# Generated by FakeRAM 2.0
VERSION 5.7 ;
BUSBITCHARS "[]" ;
PROPERTYDEFINITIONS
  MACRO width INTEGER ;
  MACRO depth INTEGER ;
  MACRO banks INTEGER ;
END PROPERTYDEFINITIONS
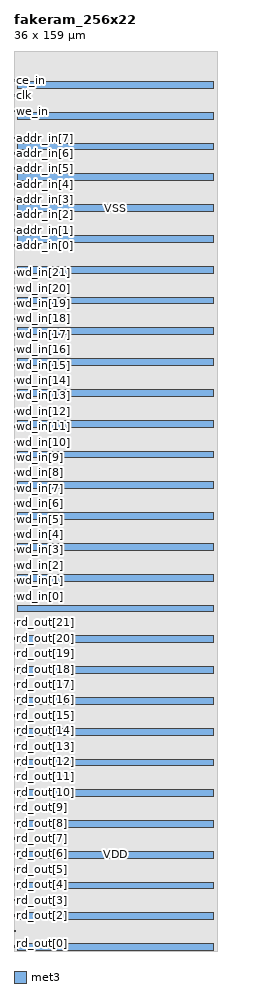
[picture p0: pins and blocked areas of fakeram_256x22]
MACRO fakeram_256x22
  PROPERTY width 22 ;
  PROPERTY depth 256 ;
  PROPERTY banks 1 ;
  FOREIGN fakeram_256x22 0 0 ;
  SYMMETRY X Y R90 ;
  SIZE 36.0000 BY 159.0000 ;
  CLASS BLOCK ;
  PIN rd_out[0]
    DIRECTION OUTPUT ;
    USE SIGNAL ;
    PORT
      LAYER met3 ;
      RECT 0.00000 0.68000 0.30000 0.98000 ;
    END
  END rd_out[0]
  PIN rd_out[1]
    DIRECTION OUTPUT ;
    USE SIGNAL ;
    PORT
      LAYER met3 ;
      RECT 0.00000 3.40000 0.30000 3.70000 ;
    END
  END rd_out[1]
  PIN rd_out[2]
    DIRECTION OUTPUT ;
    USE SIGNAL ;
    PORT
      LAYER met3 ;
      RECT 0.00000 6.12000 0.30000 6.42000 ;
    END
  END rd_out[2]
  PIN rd_out[3]
    DIRECTION OUTPUT ;
    USE SIGNAL ;
    PORT
      LAYER met3 ;
      RECT 0.00000 8.84000 0.30000 9.14000 ;
    END
  END rd_out[3]
  PIN rd_out[4]
    DIRECTION OUTPUT ;
    USE SIGNAL ;
    PORT
      LAYER met3 ;
      RECT 0.00000 11.56000 0.30000 11.86000 ;
    END
  END rd_out[4]
  PIN rd_out[5]
    DIRECTION OUTPUT ;
    USE SIGNAL ;
    PORT
      LAYER met3 ;
      RECT 0.00000 14.28000 0.30000 14.58000 ;
    END
  END rd_out[5]
  PIN rd_out[6]
    DIRECTION OUTPUT ;
    USE SIGNAL ;
    PORT
      LAYER met3 ;
      RECT 0.00000 17.00000 0.30000 17.30000 ;
    END
  END rd_out[6]
  PIN rd_out[7]
    DIRECTION OUTPUT ;
    USE SIGNAL ;
    PORT
      LAYER met3 ;
      RECT 0.00000 19.72000 0.30000 20.02000 ;
    END
  END rd_out[7]
  PIN rd_out[8]
    DIRECTION OUTPUT ;
    USE SIGNAL ;
    PORT
      LAYER met3 ;
      RECT 0.00000 22.44000 0.30000 22.74000 ;
    END
  END rd_out[8]
  PIN rd_out[9]
    DIRECTION OUTPUT ;
    USE SIGNAL ;
    PORT
      LAYER met3 ;
      RECT 0.00000 25.16000 0.30000 25.46000 ;
    END
  END rd_out[9]
  PIN rd_out[10]
    DIRECTION OUTPUT ;
    USE SIGNAL ;
    PORT
      LAYER met3 ;
      RECT 0.00000 27.88000 0.30000 28.18000 ;
    END
  END rd_out[10]
  PIN rd_out[11]
    DIRECTION OUTPUT ;
    USE SIGNAL ;
    PORT
      LAYER met3 ;
      RECT 0.00000 30.60000 0.30000 30.90000 ;
    END
  END rd_out[11]
  PIN rd_out[12]
    DIRECTION OUTPUT ;
    USE SIGNAL ;
    PORT
      LAYER met3 ;
      RECT 0.00000 33.32000 0.30000 33.62000 ;
    END
  END rd_out[12]
  PIN rd_out[13]
    DIRECTION OUTPUT ;
    USE SIGNAL ;
    PORT
      LAYER met3 ;
      RECT 0.00000 36.04000 0.30000 36.34000 ;
    END
  END rd_out[13]
  PIN rd_out[14]
    DIRECTION OUTPUT ;
    USE SIGNAL ;
    PORT
      LAYER met3 ;
      RECT 0.00000 38.76000 0.30000 39.06000 ;
    END
  END rd_out[14]
  PIN rd_out[15]
    DIRECTION OUTPUT ;
    USE SIGNAL ;
    PORT
      LAYER met3 ;
      RECT 0.00000 41.48000 0.30000 41.78000 ;
    END
  END rd_out[15]
  PIN rd_out[16]
    DIRECTION OUTPUT ;
    USE SIGNAL ;
    PORT
      LAYER met3 ;
      RECT 0.00000 44.20000 0.30000 44.50000 ;
    END
  END rd_out[16]
  PIN rd_out[17]
    DIRECTION OUTPUT ;
    USE SIGNAL ;
    PORT
      LAYER met3 ;
      RECT 0.00000 46.92000 0.30000 47.22000 ;
    END
  END rd_out[17]
  PIN rd_out[18]
    DIRECTION OUTPUT ;
    USE SIGNAL ;
    PORT
      LAYER met3 ;
      RECT 0.00000 49.64000 0.30000 49.94000 ;
    END
  END rd_out[18]
  PIN rd_out[19]
    DIRECTION OUTPUT ;
    USE SIGNAL ;
    PORT
      LAYER met3 ;
      RECT 0.00000 52.36000 0.30000 52.66000 ;
    END
  END rd_out[19]
  PIN rd_out[20]
    DIRECTION OUTPUT ;
    USE SIGNAL ;
    PORT
      LAYER met3 ;
      RECT 0.00000 55.08000 0.30000 55.38000 ;
    END
  END rd_out[20]
  PIN rd_out[21]
    DIRECTION OUTPUT ;
    USE SIGNAL ;
    PORT
      LAYER met3 ;
      RECT 0.00000 57.80000 0.30000 58.10000 ;
    END
  END rd_out[21]
  PIN wd_in[0]
    DIRECTION INPUT ;
    USE SIGNAL ;
    PORT
      LAYER met3 ;
      RECT 0.00000 62.56000 0.30000 62.86000 ;
    END
  END wd_in[0]
  PIN wd_in[1]
    DIRECTION INPUT ;
    USE SIGNAL ;
    PORT
      LAYER met3 ;
      RECT 0.00000 65.28000 0.30000 65.58000 ;
    END
  END wd_in[1]
  PIN wd_in[2]
    DIRECTION INPUT ;
    USE SIGNAL ;
    PORT
      LAYER met3 ;
      RECT 0.00000 68.00000 0.30000 68.30000 ;
    END
  END wd_in[2]
  PIN wd_in[3]
    DIRECTION INPUT ;
    USE SIGNAL ;
    PORT
      LAYER met3 ;
      RECT 0.00000 70.72000 0.30000 71.02000 ;
    END
  END wd_in[3]
  PIN wd_in[4]
    DIRECTION INPUT ;
    USE SIGNAL ;
    PORT
      LAYER met3 ;
      RECT 0.00000 73.44000 0.30000 73.74000 ;
    END
  END wd_in[4]
  PIN wd_in[5]
    DIRECTION INPUT ;
    USE SIGNAL ;
    PORT
      LAYER met3 ;
      RECT 0.00000 76.16000 0.30000 76.46000 ;
    END
  END wd_in[5]
  PIN wd_in[6]
    DIRECTION INPUT ;
    USE SIGNAL ;
    PORT
      LAYER met3 ;
      RECT 0.00000 78.88000 0.30000 79.18000 ;
    END
  END wd_in[6]
  PIN wd_in[7]
    DIRECTION INPUT ;
    USE SIGNAL ;
    PORT
      LAYER met3 ;
      RECT 0.00000 81.60000 0.30000 81.90000 ;
    END
  END wd_in[7]
  PIN wd_in[8]
    DIRECTION INPUT ;
    USE SIGNAL ;
    PORT
      LAYER met3 ;
      RECT 0.00000 84.32000 0.30000 84.62000 ;
    END
  END wd_in[8]
  PIN wd_in[9]
    DIRECTION INPUT ;
    USE SIGNAL ;
    PORT
      LAYER met3 ;
      RECT 0.00000 87.04000 0.30000 87.34000 ;
    END
  END wd_in[9]
  PIN wd_in[10]
    DIRECTION INPUT ;
    USE SIGNAL ;
    PORT
      LAYER met3 ;
      RECT 0.00000 89.76000 0.30000 90.06000 ;
    END
  END wd_in[10]
  PIN wd_in[11]
    DIRECTION INPUT ;
    USE SIGNAL ;
    PORT
      LAYER met3 ;
      RECT 0.00000 92.48000 0.30000 92.78000 ;
    END
  END wd_in[11]
  PIN wd_in[12]
    DIRECTION INPUT ;
    USE SIGNAL ;
    PORT
      LAYER met3 ;
      RECT 0.00000 95.20000 0.30000 95.50000 ;
    END
  END wd_in[12]
  PIN wd_in[13]
    DIRECTION INPUT ;
    USE SIGNAL ;
    PORT
      LAYER met3 ;
      RECT 0.00000 97.92000 0.30000 98.22000 ;
    END
  END wd_in[13]
  PIN wd_in[14]
    DIRECTION INPUT ;
    USE SIGNAL ;
    PORT
      LAYER met3 ;
      RECT 0.00000 100.64000 0.30000 100.94000 ;
    END
  END wd_in[14]
  PIN wd_in[15]
    DIRECTION INPUT ;
    USE SIGNAL ;
    PORT
      LAYER met3 ;
      RECT 0.00000 103.36000 0.30000 103.66000 ;
    END
  END wd_in[15]
  PIN wd_in[16]
    DIRECTION INPUT ;
    USE SIGNAL ;
    PORT
      LAYER met3 ;
      RECT 0.00000 106.08000 0.30000 106.38000 ;
    END
  END wd_in[16]
  PIN wd_in[17]
    DIRECTION INPUT ;
    USE SIGNAL ;
    PORT
      LAYER met3 ;
      RECT 0.00000 108.80000 0.30000 109.10000 ;
    END
  END wd_in[17]
  PIN wd_in[18]
    DIRECTION INPUT ;
    USE SIGNAL ;
    PORT
      LAYER met3 ;
      RECT 0.00000 111.52000 0.30000 111.82000 ;
    END
  END wd_in[18]
  PIN wd_in[19]
    DIRECTION INPUT ;
    USE SIGNAL ;
    PORT
      LAYER met3 ;
      RECT 0.00000 114.24000 0.30000 114.54000 ;
    END
  END wd_in[19]
  PIN wd_in[20]
    DIRECTION INPUT ;
    USE SIGNAL ;
    PORT
      LAYER met3 ;
      RECT 0.00000 116.96000 0.30000 117.26000 ;
    END
  END wd_in[20]
  PIN wd_in[21]
    DIRECTION INPUT ;
    USE SIGNAL ;
    PORT
      LAYER met3 ;
      RECT 0.00000 119.68000 0.30000 119.98000 ;
    END
  END wd_in[21]
  PIN addr_in[0]
    DIRECTION INPUT ;
    USE SIGNAL ;
    PORT
      LAYER met3 ;
      RECT 0.00000 124.44000 0.30000 124.74000 ;
    END
  END addr_in[0]
  PIN addr_in[1]
    DIRECTION INPUT ;
    USE SIGNAL ;
    PORT
      LAYER met3 ;
      RECT 0.00000 127.16000 0.30000 127.46000 ;
    END
  END addr_in[1]
  PIN addr_in[2]
    DIRECTION INPUT ;
    USE SIGNAL ;
    PORT
      LAYER met3 ;
      RECT 0.00000 129.88000 0.30000 130.18000 ;
    END
  END addr_in[2]
  PIN addr_in[3]
    DIRECTION INPUT ;
    USE SIGNAL ;
    PORT
      LAYER met3 ;
      RECT 0.00000 132.60000 0.30000 132.90000 ;
    END
  END addr_in[3]
  PIN addr_in[4]
    DIRECTION INPUT ;
    USE SIGNAL ;
    PORT
      LAYER met3 ;
      RECT 0.00000 135.32000 0.30000 135.62000 ;
    END
  END addr_in[4]
  PIN addr_in[5]
    DIRECTION INPUT ;
    USE SIGNAL ;
    PORT
      LAYER met3 ;
      RECT 0.00000 138.04000 0.30000 138.34000 ;
    END
  END addr_in[5]
  PIN addr_in[6]
    DIRECTION INPUT ;
    USE SIGNAL ;
    PORT
      LAYER met3 ;
      RECT 0.00000 140.76000 0.30000 141.06000 ;
    END
  END addr_in[6]
  PIN addr_in[7]
    DIRECTION INPUT ;
    USE SIGNAL ;
    PORT
      LAYER met3 ;
      RECT 0.00000 143.48000 0.30000 143.78000 ;
    END
  END addr_in[7]
  PIN we_in
    DIRECTION INPUT ;
    USE SIGNAL ;
    PORT
      LAYER met3 ;
      RECT 0.00000 148.24000 0.30000 148.54000 ;
    END
  END we_in
  PIN clk
    DIRECTION INPUT ;
    USE SIGNAL ;
    PORT
      LAYER met3 ;
      RECT 0.00000 150.96000 0.30000 151.26000 ;
    END
  END clk
  PIN ce_in
    DIRECTION INPUT ;
    USE SIGNAL ;
    PORT
      LAYER met3 ;
      RECT 0.00000 153.68000 0.30000 153.98000 ;
    END
  END ce_in
  PIN VDD
    DIRECTION INOUT ;
    USE POWER ;
    PORT
      LAYER met3 ;
      RECT 0.68000 5.52000 35.32000 6.72000 ;
      RECT 0.68000 16.40000 35.32000 17.60000 ;
      RECT 0.68000 27.28000 35.32000 28.48000 ;
      RECT 0.68000 38.16000 35.32000 39.36000 ;
      RECT 0.68000 49.04000 35.32000 50.24000 ;
      RECT 0.68000 59.92000 35.32000 61.12000 ;
      RECT 0.68000 70.80000 35.32000 72.00000 ;
      RECT 0.68000 81.68000 35.32000 82.88000 ;
      RECT 0.68000 92.56000 35.32000 93.76000 ;
      RECT 0.68000 103.44000 35.32000 104.64000 ;
      RECT 0.68000 114.32000 35.32000 115.52000 ;
      RECT 0.68000 125.20000 35.32000 126.40000 ;
      RECT 0.68000 136.08000 35.32000 137.28000 ;
      RECT 0.68000 146.96000 35.32000 148.16000 ;
    END
  END VDD
  PIN VSS
    DIRECTION INOUT ;
    USE GROUND ;
    PORT
      LAYER met3 ;
      RECT 0.68000 0.08000 35.32000 1.28000 ;
      RECT 0.68000 10.96000 35.32000 12.16000 ;
      RECT 0.68000 21.84000 35.32000 23.04000 ;
      RECT 0.68000 32.72000 35.32000 33.92000 ;
      RECT 0.68000 43.60000 35.32000 44.80000 ;
      RECT 0.68000 54.48000 35.32000 55.68000 ;
      RECT 0.68000 65.36000 35.32000 66.56000 ;
      RECT 0.68000 76.24000 35.32000 77.44000 ;
      RECT 0.68000 87.12000 35.32000 88.32000 ;
      RECT 0.68000 98.00000 35.32000 99.20000 ;
      RECT 0.68000 108.88000 35.32000 110.08000 ;
      RECT 0.68000 119.76000 35.32000 120.96000 ;
      RECT 0.68000 130.64000 35.32000 131.84000 ;
      RECT 0.68000 141.52000 35.32000 142.72000 ;
      RECT 0.68000 152.40000 35.32000 153.60000 ;
    END
  END VSS
  OBS
    LAYER met1 ;
    RECT 0 0 36.00000 159.00000 ;
    LAYER met2 ;
    RECT 0 0 36.00000 159.00000 ;
    LAYER met3 ;
    RECT 0 0 36.00000 159.00000 ;
  END
END fakeram_256x22

END LIBRARY
